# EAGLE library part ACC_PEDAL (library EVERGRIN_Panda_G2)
Accelerator pedal

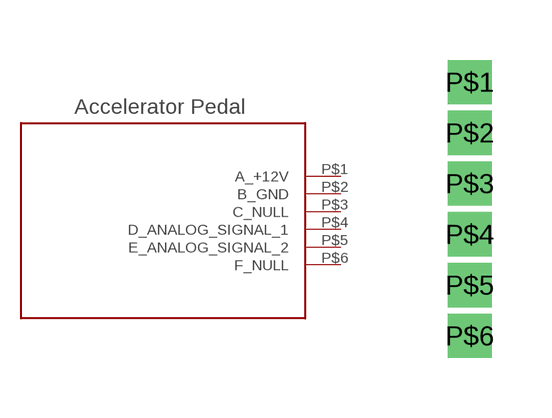
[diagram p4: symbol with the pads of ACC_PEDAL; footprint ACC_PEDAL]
Designator prefix -

## ACC_PEDAL  [ACC_PEDAL]
P$1  A_+12V
P$2  B_GND
P$3  C_NULL
P$4  D_ANALOG_SIGNAL_1
P$5  E_ANALOG_SIGNAL_2
P$6  F_NULL

## Footprint ACC_PEDAL (pad centres in mm)
drill 0.6 square: P$1 5.08,11.43; P$2 5.08,10.16; P$3 5.08,8.89; P$4 5.08,7.62; P$5 5.08,6.35; P$6 5.08,5.08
